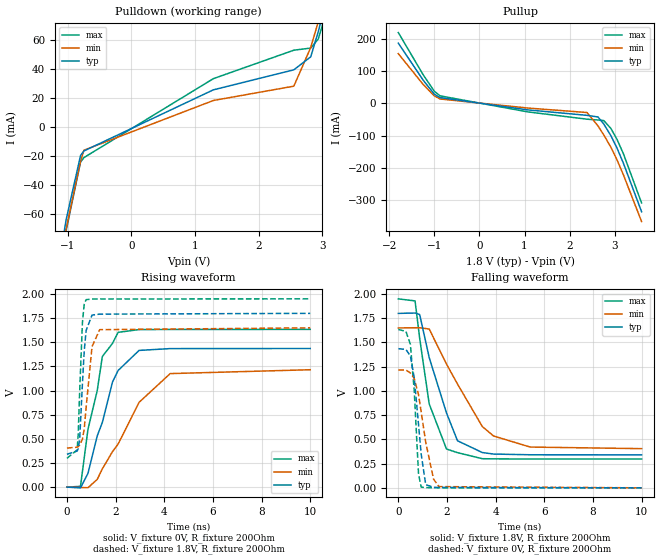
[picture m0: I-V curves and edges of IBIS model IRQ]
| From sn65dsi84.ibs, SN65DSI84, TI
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|   Model
[Model]   IRQ
Model_type   Output
Polarity   Non-Inverting
Vmeas = 0.9
Vref = 0
Cref = 1pF
Rref = 10000
|   typ   min   max
C_comp   0.2695pF   0.2096pF   0.3469pF
[Voltage Range]   1.8   1.65   1.95
[Temperature Range]   27   125   -40
[Pullup Reference]   1.8   1.65   1.95
[Pulldown Reference]   -0   -0   -0
[Power Clamp Reference]   1.8   1.65   1.95
[GND Clamp Reference]   -0   -0   -0
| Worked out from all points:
|   slope of the pulldown table from 0 to 0.27 V, typ, clamps not added: 46.5 ohm
|   slope of the pullup table from 0 to 0.27 V, typ, clamps not added: 50.4 ohm
|   falling waveform, V_fixture 1.8V, R_fixture 200Ohm: 20-80 % time 1.04ns typ, 1.66ns min, 767ps max; typ from 1.8 V to 0.341 V
|   rising waveform, V_fixture 0V, R_fixture 200Ohm: 20-80 % time 974ps typ, 1.78ns min, 693ps max; typ from 0 V to 1.44 V
|   rising waveform, V_fixture 1.8V, R_fixture 200Ohm: 20-80 % time 183ps typ, 265ps min, 143ps max; typ from 0.341 V to 1.8 V
|   falling waveform, V_fixture 0V, R_fixture 200Ohm: 20-80 % time 314ps typ, 477ps min, 223ps max; typ from 1.44 V to 0 V
[Pulldown]
|   Voltage   I(typ)   I(min)   I(max)
-1.8V     -333mA     -309.7mA   -367.4mA
-1.157V   -99.32mA   -101.7mA   -114.1mA
-1.022V   -63.77mA   -69.97mA   -71.37mA
-795.6mV  -19.54mA   -23.42mA   -24.05mA
-741.6mV  -16.41mA   -15.88mA   -20.97mA
1.289V    25.61mA    18.28mA    33.3mA
2.552V    39.37mA    28.13mA    52.87mA
2.817V    48.31mA    54.73mA    54.33mA
2.936V    65.68mA    72.46mA    60.58mA
3.022V    80.75mA    86.06mA    73.32mA
3.071V    89.66mA    93.88mA    82.17mA
3.595V    192.5mA    182mA      195.1mA
[Pullup]
|   Voltage   I(typ)   I(min)   I(max)
-1.8V     186.6mA    154.1mA    219.3mA
-1.249V   72.09mA    58.72mA    88.81mA
-1.001V   28.48mA    23.16mA    37.43mA
-871.2mV  17.99mA    13.71mA    23.36mA
1.062V    -19.91mA   -14.15mA   -26mA
2.385V    -36.91mA   -28.19mA   -48.82mA
2.628V    -41.93mA   -69.51mA   -51.27mA
2.758V    -64.03mA   -97.92mA   -53.23mA
2.914V    -99.8mA    -135.6mA   -77.48mA
3.049V    -137.9mA   -174.4mA   -111mA
3.19V     -184.6mA   -220.4mA   -155.2mA
3.595V    -335.4mA   -365.7mA   -308.2mA
[Ramp]
R_load = 200
|   typ   min   max
dV/dt_r   0.861892/9.76011e-10   0.729729/1.75843e-09   0.980234/6.94517e-10
dV/dt_f   0.875592/1.04381e-09   0.74723/1.6614e-09   0.991498/7.69733e-10
[Falling Waveform]
V_fixture = 1.8V
V_fixture_min = 1.65V
V_fixture_max = 1.95V
R_fixture = 200Ohm
C_fixture = 0F
|   Time   V(typ)   V(min)   V(max)
0s        1.8V       1.65V      1.95V
688.8ps   1.804V     1.652V     1.929V
878.6ps   1.788V     1.652V     1.542V
1.269ns   1.345V     1.639V     866.8mV
1.98ns    773.2mV    1.278V     400.9mV
2.433ns   485.8mV    1.071V     363.2mV
3.452ns   364.5mV    633mV      300.9mV
3.913ns   348.7mV    535.4mV    299.1mV
5.421ns   341.3mV    420.9mV    297.5mV
10ns      340.7mV    404.5mV    297.5mV
[Rising Waveform]
V_fixture = 0V
V_fixture_min = 0V
V_fixture_max = 0V
R_fixture = 200Ohm
C_fixture = 0F
|   Time   V(typ)   V(min)   V(max)
0s        62.16nV    120uV      254.8nV
556.8ps   -7.315mV   -3.762mV   8.38mV
864.8ps   142.5mV    -5.909mV   600mV
1.244ns   529.9mV    79.93mV    998.9mV
1.455ns   669.9mV    189mV      1.353V
1.873ns   1.089V     368.3mV    1.489V
2.103ns   1.208V     446.3mV    1.603V
2.964ns   1.416V     878.1mV    1.632V
4.245ns   1.435V     1.176V     1.633V
10ns      1.436V     1.216V     1.634V
[Rising Waveform]
V_fixture = 1.8V
V_fixture_min = 1.65V
V_fixture_max = 1.95V
R_fixture = 200Ohm
C_fixture = 0F
|   Time   V(typ)   V(min)   V(max)
0s        340.7mV    404.5mV    297.5mV
420ps     373.3mV    413.6mV    387.1mV
461.5ps   396.6mV    418.6mV    540.7mV
524ps     500.2mV    435.1mV    996.3mV
636.5ps   1.069V     496.6mV    1.705V
710.1ps   1.41V      602.3mV    1.896V
788.7ps   1.623V     825.1mV    1.942V
1.031ns   1.782V     1.456V     1.948V
1.347ns   1.792V     1.631V     1.949V
10ns      1.8V       1.65V      1.95V
[Falling Waveform]
|Gnd
V_fixture = 0V
V_fixture_min = 0V
V_fixture_max = 0V
R_fixture = 200Ohm
C_fixture = 0F
|   Time   V(typ)   V(min)   V(max)
0s        1.436V     1.216V     1.634V
311.8ps   1.428V     1.216V     1.615V
496.9ps   1.361V     1.185V     1.481V
654.9ps   1.137V     1.127V     1.001V
831.4ps   651.9mV    961.3mV    141.8mV
942.1ps   345mV      780.9mV    7.068mV
1.127ns   32.18mV    470.2mV    3.116mV
1.45ns    5.693mV    88.88mV    790.7uV
1.674ns   4.342mV    12.77mV    770uV
10ns      62.02nV    120.2uV    254.7nV
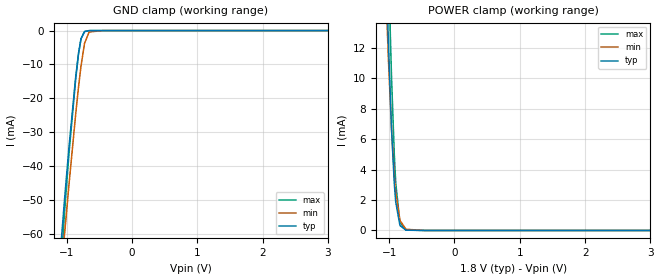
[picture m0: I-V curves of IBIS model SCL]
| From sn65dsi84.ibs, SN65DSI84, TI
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|   Model
[Model]   SCL
Model_type   Input
Vinl = 0.54
Vinh = 1.26
|   typ   min   max
C_comp   0.1891pF   0.1144pF   0.2684pF
[Voltage Range]   1.8   1.65   1.95
[Temperature Range]   27   125   -40
[Power Clamp Reference]   1.8   1.65   1.95
[GND Clamp Reference]   -0   -0   -0
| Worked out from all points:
|   GND clamp passes 1 mA (typ) near -0.75 V on its own axis
|   POWER clamp passes 1 mA (typ) near -0.87 V on its own axis
[GND Clamp]
|   Voltage   I(typ)   I(min)   I(max)
-1.8V     -308mA     -292.1mA   -326.9mA
-1.141V   -77.87mA   -84.93mA   -86.79mA
-1.087V   -63.42mA   -72.55mA   -69.8mA
-1.033V   -50.21mA   -60.55mA   -54.19mA
-963mV    -34.35mA   -45.43mA   -36.28mA
-860.4mV  -13.64mA   -24.61mA   -14.26mA
-817.2mV  -6.639mA   -16.67mA   -6.881mA
-779.4mV  -2.431mA   -10.48mA   -2.438mA
-725.4mV  -281.1uA   -3.796mA   -288.1uA
-655.2mV  -11.59uA   -427.7uA   -18.55uA
-450mV    -689.2pA   -165.9nA   -3.991nA
3.595V    0A         0A         0A
[POWER Clamp]
|   Voltage   I(typ)   I(min)   I(max)
-1.8V     160.5mA    134.1mA    187.1mA
-1.071V   21.35mA    18.46mA    28.34mA
-1.044V   17.18mA    15.11mA    23.34mA
-1.033V   15.58mA    13.84mA    21.4mA
-1.012V   12.54mA    11.4mA     17.66mA
-963mV    6.674mA    6.673mA    10.11mA
-919.8mV  3.033mA    3.571mA    4.947mA
-898.2mV  1.861mA    2.46mA     3.112mA
-833.4mV  322.4uA    654.5uA    513uA
-741.6mV  20.48uA    76.69uA    25.35uA
-450mV    1.308nA    64.32nA    622.8pA
3.595V    0A         0A         0A
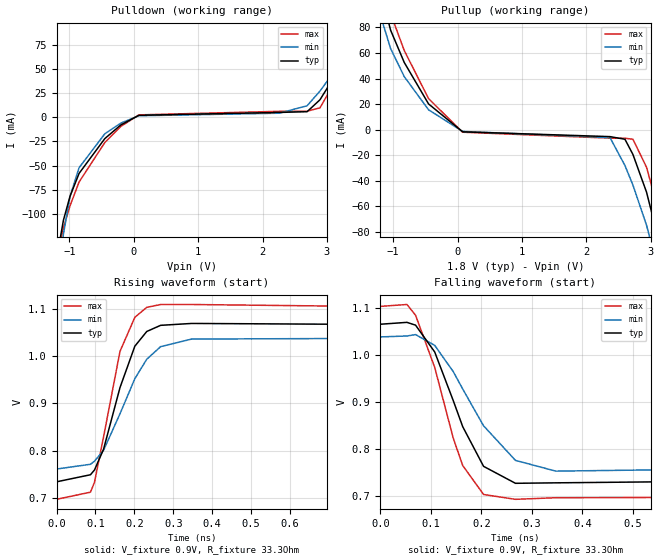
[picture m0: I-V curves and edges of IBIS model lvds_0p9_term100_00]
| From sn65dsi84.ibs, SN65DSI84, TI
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|   Model
[Model]   lvds_0p9_term100_00
Model_type   Output
Polarity   Non-Inverting
Vmeas = 0.9
Vref = 0.9
Cref = 1pF
Rref = 50
|   typ   min   max
C_comp   0.4797pF   0.3035pF   0.7186pF
[Voltage Range]   1.8   1.65   1.95
[Temperature Range]   27   125   -40
[Pullup Reference]   1.8   1.65   1.95
[Pulldown Reference]   -0   -0   -0
[Power Clamp Reference]   1.8   1.65   1.95
[GND Clamp Reference]   -0   -0   -0
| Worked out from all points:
|   slope of the pulldown table from 0 to 0.27 V, typ, clamps not added: 62.1 ohm
|   slope of the pullup table from 0 to 0.27 V, typ, clamps not added: 74.8 ohm
|   falling waveform, V_fixture 0.9V, R_fixture 33.3Ohm: 20-80 % time 71.2ps typ, 91.9ps min, 64.4ps max; typ from 1.06 V to 0.734 V
|   rising waveform, V_fixture 0.9V, R_fixture 33.3Ohm: 20-80 % time 70.3ps typ, 92ps min, 57.9ps max; typ from 0.734 V to 1.07 V
[Pulldown]
|   Voltage   I(typ)   I(min)   I(max)
-1.8V     -663.2mA   -698.2mA   -653.8mA
-1.147V   -127.1mA   -150.5mA   -131.3mA
-1.093V   -106.7mA   -121.2mA   -114.7mA
-990mV    -81.79mA   -82mA      -91.67mA
-849.6mV  -58.11mA   -52.24mA   -67.04mA
-450mV    -22.08mA   -17.11mA   -26.18mA
-201.6mV  -7.915mA   -6.02mA    -9.483mA
79.2mV    2.069mA    1.602mA    2.511mA
2.261V    5.055mA    4.263mA    6.221mA
2.693V    5.825mA    11.99mA    6.265mA
2.893V    18.2mA     27.2mA     9.845mA
3.595V    93.41mA    90.88mA    91.31mA
[Pullup]
|   Voltage   I(typ)   I(min)   I(max)
-1.8V     238.4mA    204.8mA    267.3mA
-1.406V   147.9mA    123.5mA    169.1mA
-1.039V   77.79mA    63.39mA    90.82mA
-828mV    52.64mA    41.57mA    61.97mA
-450mV    20.19mA    15.6mA     24.32mA
79.2mV    -1.629mA   -1.318mA   -1.926mA
2.369V    -5.381mA   -6.136mA   -6.594mA
2.601V    -7.44mA    -27.97mA   -6.64mA
2.725V    -19.31mA   -43.25mA   -7.414mA
2.936V    -48.73mA   -74.55mA   -29.26mA
3.13V     -87.11mA   -112.3mA   -64.81mA
3.595V    -191.5mA   -213.4mA   -169.3mA
[Ramp]
R_load = 33.3
|   typ   min   max
dV/dt_r   0.198677/7.02874e-11   0.166166/9.20302e-11   0.243302/5.78686e-11
dV/dt_f   0.198434/7.11772e-11   0.166017/9.18975e-11   0.24332/6.44189e-11
[Falling Waveform]
V_fixture = 0.9V
V_fixture_min = 0.9V
V_fixture_max = 0.9V
R_fixture = 33.3Ohm
C_fixture = 0F
|   Time   V(typ)   V(min)   V(max)
0s        1.065V     1.038V     1.103V
52.82ps   1.069V     1.04V      1.107V
69.85ps   1.063V     1.043V     1.084V
107.7ps   1.006V     1.02V      973.2mV
144.4ps   902.5mV    964.2mV    822.6mV
163.1ps   847.1mV    927.2mV    764.4mV
204.4ps   762.6mV    848.9mV    702.7mV
267.5ps   726.5mV    775.3mV    692.4mV
347.4ps   727.5mV    752.4mV    695.8mV
1ns       734.4mV    761.4mV    697.4mV
[Rising Waveform]
V_fixture = 0.9V
V_fixture_min = 0.9V
V_fixture_max = 0.9V
R_fixture = 33.3Ohm
C_fixture = 0F
|   Time   V(typ)   V(min)   V(max)
0s        734.5mV    761.5mV    697.5mV
87.21ps   749.4mV    771.5mV    712.6mV
97.65ps   759.6mV    778.1mV    733.7mV
120.8ps   803.1mV    801mV      828.9mV
163.1ps   933.5mV    878.2mV    1.01V
201.3ps   1.021V     952.4mV    1.082V
231.9ps   1.052V     993.4mV    1.103V
267.5ps   1.065V     1.02V      1.109V
347.4ps   1.069V     1.036V     1.109V
1ns       1.066V     1.038V     1.103V
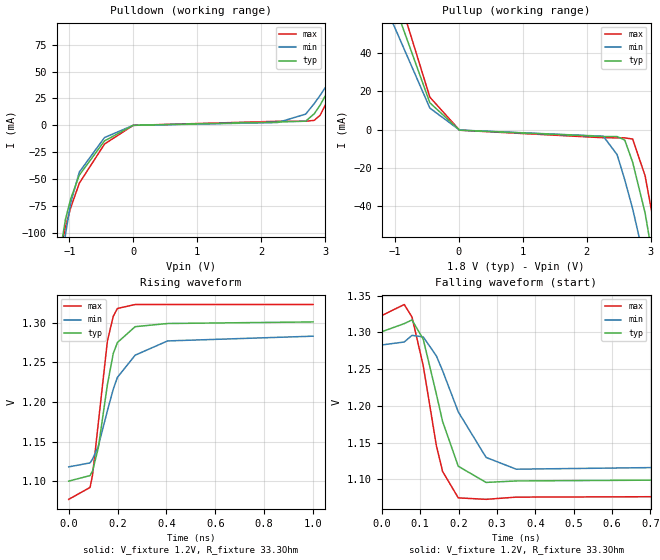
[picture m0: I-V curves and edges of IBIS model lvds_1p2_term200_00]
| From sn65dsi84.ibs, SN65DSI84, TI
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|   Model
[Model]   lvds_1p2_term200_00
Model_type   Output
Polarity   Non-Inverting
Vmeas = 1.2
Vref = 1.2
Cref = 1pF
Rref = 50
|   typ   min   max
C_comp   0.4797pF   0.3035pF   0.7186pF
[Voltage Range]   1.8   1.65   1.95
[Temperature Range]   27   125   -40
[Pullup Reference]   1.8   1.65   1.95
[Pulldown Reference]   -0   -0   -0
[Power Clamp Reference]   1.8   1.65   1.95
[GND Clamp Reference]   -0   -0   -0
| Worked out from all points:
|   slope of the pulldown table from 0 to 0.27 V, typ, clamps not added: 103 ohm
|   slope of the pullup table from 0 to 0.27 V, typ, clamps not added: 114 ohm
|   falling waveform, V_fixture 1.2V, R_fixture 33.3Ohm: 20-80 % time 56.1ps typ, 82.7ps min, 49.8ps max; typ from 1.3 V to 1.1 V
|   rising waveform, V_fixture 1.2V, R_fixture 33.3Ohm: 20-80 % time 62.1ps typ, 110ps min, 51.8ps max; typ from 1.1 V to 1.3 V
[Pulldown]
|   Voltage   I(typ)   I(min)   I(max)
-1.8V     -662.7mA   -697.8mA   -653.1mA
-1.13V    -112.7mA   -137.9mA   -115.4mA
-1.06V    -87.36mA   -101.6mA   -94.27mA
-979.2mV  -68.51mA   -72.26mA   -76.75mA
-844.2mV  -46.38mA   -43.5mA    -53.83mA
-450mV    -14.51mA   -11.38mA   -17.44mA
-1.8mV    -33.52uA   -25.45uA   -40.79uA
2.255V    3.03mA     2.555mA    3.73mA
2.693V    3.824mA    10.38mA    3.762mA
2.828V    10.8mA     20.31mA    4.629mA
2.92V     18.84mA    27.88mA    9.431mA
3.595V    91.51mA    89.23mA    89.04mA
[Pullup]
|   Voltage   I(typ)   I(min)   I(max)
-1.8V     228.4mA    197.8mA    256.2mA
-1.384V   134.8mA    113.2mA    154.9mA
-1.022V   67.23mA    55.25mA    78.93mA
-450mV    14.1mA     11.33mA    17.03mA
14.4mV    -217.5uA   -179.5uA   -252uA
2.261V    -3.537mA   -3.389mA   -4.176mA
2.477V    -3.566mA   -13.07mA   -4.203mA
2.596V    -5.396mA   -26.18mA   -4.219mA
2.72V     -17.05mA   -41.41mA   -4.896mA
2.914V    -43.54mA   -69.73mA   -24.09mA
3.152V    -90.28mA   -115.7mA   -67.42mA
3.595V    -190.1mA   -212.3mA   -167.4mA
[Ramp]
R_load = 33.3
|   typ   min   max
dV/dt_r   0.120214/6.20859e-11  0.0988831/1.09518e-10   0.147657/5.18256e-11
dV/dt_f   0.120287/5.61186e-11  0.0991023/8.2679e-11   0.147675/4.97948e-11
[Falling Waveform]
V_fixture = 1.2V
V_fixture_min = 1.2V
V_fixture_max = 1.2V
R_fixture = 33.3Ohm
C_fixture = 0F
|   Time   V(typ)   V(min)   V(max)
0s        1.301V     1.283V     1.323V
58.42ps   1.312V     1.287V     1.338V
78.5ps    1.317V     1.296V     1.321V
107.8ps   1.291V     1.294V     1.255V
142.2ps   1.216V     1.268V     1.146V
158.3ps   1.179V     1.248V     1.111V
199.2ps   1.118V     1.192V     1.075V
271.7ps   1.096V     1.13V      1.073V
350.3ps   1.098V     1.114V     1.076V
1ns       1.1V       1.118V     1.077V
[Rising Waveform]
V_fixture = 1.2V
V_fixture_min = 1.2V
V_fixture_max = 1.2V
R_fixture = 33.3Ohm
C_fixture = 0F
|   Time   V(typ)   V(min)   V(max)
0s        1.1V       1.118V     1.077V
87.14ps   1.107V     1.123V     1.092V
97.58ps   1.113V     1.128V     1.108V
120.9ps   1.142V     1.144V     1.173V
158.3ps   1.222V     1.189V     1.277V
182.1ps   1.261V     1.216V     1.308V
199.2ps   1.275V     1.231V     1.318V
271.7ps   1.295V     1.259V     1.323V
404.4ps   1.299V     1.277V     1.323V
1ns       1.301V     1.283V     1.323V
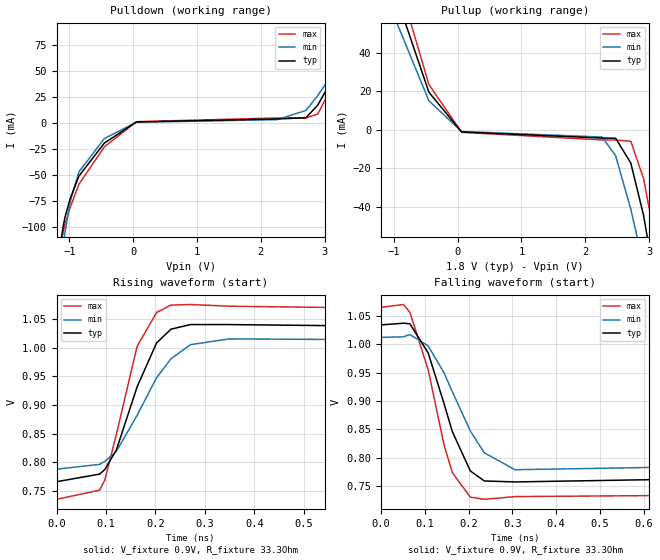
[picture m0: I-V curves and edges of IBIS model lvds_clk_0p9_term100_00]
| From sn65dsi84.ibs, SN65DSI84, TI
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|   Model
[Model]   lvds_clk_0p9_term100_00
Model_type   Output
Polarity   Non-Inverting
Vmeas = 0.9
Vref = 0.9
Cref = 1pF
Rref = 50
|   typ   min   max
C_comp   0.4797pF   0.3035pF   0.7186pF
[Voltage Range]   1.8   1.65   1.95
[Temperature Range]   27   125   -40
[Pullup Reference]   1.8   1.65   1.95
[Pulldown Reference]   -0   -0   -0
[Power Clamp Reference]   1.8   1.65   1.95
[GND Clamp Reference]   -0   -0   -0
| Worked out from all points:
|   slope of the pulldown table from 0 to 0.27 V, typ, clamps not added: 76.3 ohm
|   slope of the pullup table from 0 to 0.27 V, typ, clamps not added: 92.1 ohm
|   falling waveform, V_fixture 0.9V, R_fixture 33.3Ohm: 20-80 % time 65.1ps typ, 82.8ps min, 58.7ps max; typ from 1.03 V to 0.766 V
|   rising waveform, V_fixture 0.9V, R_fixture 33.3Ohm: 20-80 % time 65.2ps typ, 87.1ps min, 53.3ps max; typ from 0.766 V to 1.03 V
[Pulldown]
|   Voltage   I(typ)   I(min)   I(max)
-1.8V     -662.6mA   -697.8mA   -653.1mA
-1.13V    -112.8mA   -137.8mA   -115.6mA
-1.093V   -98.16mA   -117.2mA   -103.8mA
-1.066V   -89.99mA   -104.3mA   -97.08mA
-984.6mV  -72.24mA   -75.1mA    -80.79mA
-849.6mV  -50.82mA   -46.82mA   -58.68mA
-450mV    -19.06mA   -14.73mA   -22.65mA
52.2mV    1.211mA    935.7uA    1.469mA
2.261V    4.084mA    3.439mA    5.042mA
2.709V    5.234mA    12.28mA    5.089mA
2.893V    17.31mA    26.43mA    8.728mA
3.595V    92.49mA    90.08mA    90.23mA
[Pullup]
|   Voltage   I(typ)   I(min)   I(max)
-1.8V     237.6mA    203.9mA    266.4mA
-1.411V   148mA      123.6mA    169.4mA
-1.039V   76.94mA    62.59mA    89.89mA
-450mV    19.51mA    15.04mA    23.53mA
63mV      -1.148mA   -931.1uA   -1.345mA
2.266V    -4.318mA   -3.801mA   -5.289mA
2.477V    -4.419mA   -13.5mA    -5.359mA
2.714V    -17.27mA   -41.2mA    -6.003mA
2.914V    -44.4mA    -70.26mA   -25.28mA
3.103V    -80.8mA    -106.2mA   -58.44mA
3.163V    -93.5mA    -118.6mA   -70.88mA
3.595V    -191.2mA   -213.1mA   -168.7mA
[Ramp]
R_load = 33.3
|   typ   min   max
dV/dt_r   0.160952/6.51744e-11   0.134803/8.70959e-11   0.197638/5.32723e-11
dV/dt_f   0.160717/6.51386e-11   0.134547/8.28133e-11   0.19766/5.86534e-11
[Falling Waveform]
V_fixture = 0.9V
V_fixture_min = 0.9V
V_fixture_max = 0.9V
R_fixture = 33.3Ohm
C_fixture = 0F
|   Time   V(typ)   V(min)   V(max)
0s        1.034V     1.012V     1.065V
51.23ps   1.037V     1.013V     1.07V
65.99ps   1.036V     1.017V     1.056V
107.7ps   984.6mV    997mV      954.9mV
144.3ps   894.3mV    949mV      821.2mV
163ps     845.6mV    916mV      773.3mV
204.1ps   776.4mV    846.8mV    730.2mV
235.9ps   758.8mV    808.5mV    726.4mV
306.1ps   757.1mV    778.6mV    731.2mV
1ns       766mV      787.7mV    735.2mV
[Rising Waveform]
V_fixture = 0.9V
V_fixture_min = 0.9V
V_fixture_max = 0.9V
R_fixture = 33.3Ohm
C_fixture = 0F
|   Time   V(typ)   V(min)   V(max)
0s        766mV      787.8mV    735.3mV
87.21ps   779.3mV    796.3mV    751.3mV
97.67ps   787.3mV    801.4mV    768.8mV
120.9ps   821.1mV    818.7mV    848mV
163ps     931.4mV    881.8mV    1.002V
202.3ps   1.008V     947.3mV    1.061V
231.5ps   1.032V     980.4mV    1.074V
271ps     1.04V      1.005V     1.075V
349.4ps   1.04V      1.015V     1.072V
1ns       1.034V     1.012V     1.065V
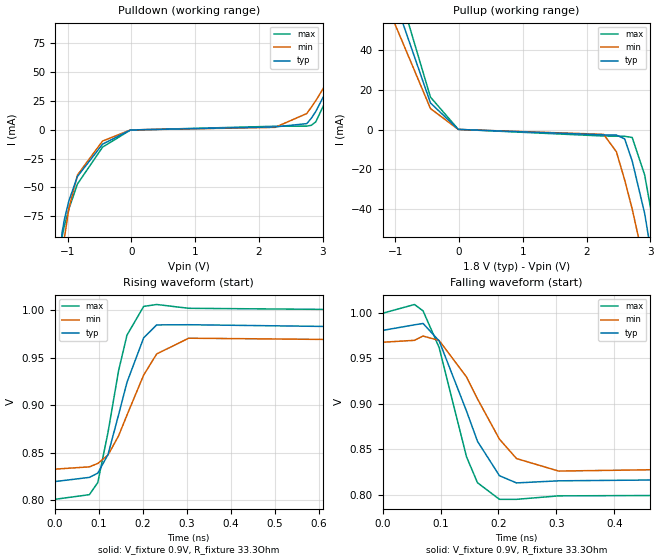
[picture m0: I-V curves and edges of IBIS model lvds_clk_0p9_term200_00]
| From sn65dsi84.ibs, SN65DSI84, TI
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|   Model
[Model]   lvds_clk_0p9_term200_00
Model_type   Output
Polarity   Non-Inverting
Vmeas = 0.9
Vref = 0.9
Cref = 1pF
Rref = 50
|   typ   min   max
C_comp   0.4797pF   0.3035pF   0.7186pF
[Voltage Range]   1.8   1.65   1.95
[Temperature Range]   27   125   -40
[Pullup Reference]   1.8   1.65   1.95
[Pulldown Reference]   -0   -0   -0
[Power Clamp Reference]   1.8   1.65   1.95
[GND Clamp Reference]   -0   -0   -0
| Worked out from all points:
|   slope of the pulldown table from 0 to 0.27 V, typ, clamps not added: 127 ohm
|   slope of the pullup table from 0 to 0.27 V, typ, clamps not added: 154 ohm
|   falling waveform, V_fixture 0.9V, R_fixture 33.3Ohm: 20-80 % time 55.1ps typ, 68.7ps min, 47.4ps max; typ from 0.981 V to 0.82 V
|   rising waveform, V_fixture 0.9V, R_fixture 33.3Ohm: 20-80 % time 56.7ps typ, 76.8ps min, 47.6ps max; typ from 0.82 V to 0.981 V
[Pulldown]
|   Voltage   I(typ)   I(min)   I(max)
-1.8V     -662.3mA   -697.6mA   -652.6mA
-1.087V   -89.57mA   -111.6mA   -93.11mA
-1.049V   -77.61mA   -93.69mA   -83.11mA
-979.2mV  -61.67mA   -68.27mA   -68.63mA
-844.2mV  -40.44mA   -39.16mA   -46.96mA
-450mV    -12.48mA   -9.755mA   -15.02mA
-12.6mV   -201.7uA   -153.6uA   -245.1uA
2.255V    2.45mA     2.064mA    3.025mA
2.752V    5.292mA    14.03mA    3.13mA
2.822V    9.84mA     19.42mA    3.81mA
2.893V    15.8mA     25.15mA    6.822mA
3.595V    90.97mA    88.75mA    88.4mA
[Pullup]
|   Voltage   I(typ)   I(min)   I(max)
-1.8V     227.7mA    196.9mA    255.5mA
-1.39V    135.1mA    113.1mA    155.4mA
-1.022V   66.49mA    54.34mA    78.23mA
-450mV    13.5mA     10.68mA    16.42mA
-12.6mV   167.1uA    131.7uA    196.7uA
2.266V    -2.587mA   -2.309mA   -3.171mA
2.466V    -2.672mA   -11.08mA   -3.224mA
2.596V    -4.606mA   -25.31mA   -3.294mA
2.714V    -15.73mA   -39.89mA   -3.909mA
2.909V    -42.04mA   -68.08mA   -22.68mA
3.136V    -86.3mA    -111.7mA   -63.45mA
3.595V    -189.8mA   -212mA     -167mA
[Ramp]
R_load = 33.3
|   typ   min   max
dV/dt_r   0.096664/5.66709e-11  0.0809776/7.68463e-11   0.119148/4.75678e-11
dV/dt_f   0.0966321/5.51163e-11  0.0809772/6.86759e-11   0.119149/4.73592e-11
[Falling Waveform]
V_fixture = 0.9V
V_fixture_min = 0.9V
V_fixture_max = 0.9V
R_fixture = 33.3Ohm
C_fixture = 0F
|   Time   V(typ)   V(min)   V(max)
0s        980.6mV    967.6mV    999.4mV
55.03ps   986.7mV    969.7mV    1.009V
69.85ps   988.2mV    974.4mV    1.002V
97.68ps   969mV      969.5mV    961.7mV
144.9ps   892.1mV    929.5mV    841.9mV
163.9ps   858.9mV    905.4mV    813.5mV
201.8ps   821.2mV    861.3mV    795.3mV
231.3ps   813.3mV    840mV      795.3mV
304ps     815.6mV    826.3mV    799.1mV
1ns       819.5mV    832.6mV    800.8mV
[Rising Waveform]
V_fixture = 0.9V
V_fixture_min = 0.9V
V_fixture_max = 0.9V
R_fixture = 33.3Ohm
C_fixture = 0F
|   Time   V(typ)   V(min)   V(max)
0s        819.5mV    832.6mV    800.8mV
78.53ps   823.9mV    835mV      805.7mV
97.68ps   828.4mV    838.6mV    818.5mV
120.9ps   848.1mV    847.5mV    871.5mV
144.9ps   889.9mV    867.7mV    936.4mV
163.9ps   924mV      889.5mV    973.7mV
201.8ps   970.9mV    931.7mV    1.004V
231.3ps   984.5mV    953.9mV    1.006V
304ps     984.7mV    970.5mV    1.002V
1ns       980.6mV    967.6mV    999.4mV
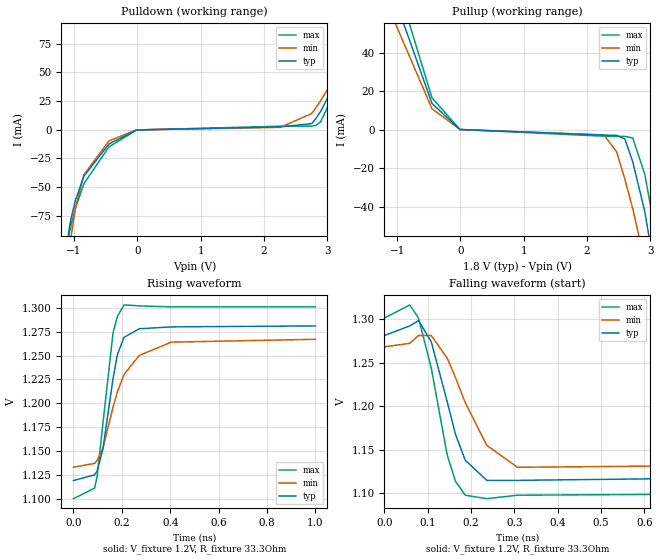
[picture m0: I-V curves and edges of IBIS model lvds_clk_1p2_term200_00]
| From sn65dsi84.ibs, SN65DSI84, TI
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|   Model
[Model]   lvds_clk_1p2_term200_00
Model_type   Output
Polarity   Non-Inverting
Vmeas = 1.2
Vref = 1.2
Cref = 1pF
Rref = 50
|   typ   min   max
C_comp   0.4797pF   0.3035pF   0.7186pF
[Voltage Range]   1.8   1.65   1.95
[Temperature Range]   27   125   -40
[Pullup Reference]   1.8   1.65   1.95
[Pulldown Reference]   -0   -0   -0
[Power Clamp Reference]   1.8   1.65   1.95
[GND Clamp Reference]   -0   -0   -0
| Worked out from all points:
|   slope of the pulldown table from 0 to 0.27 V, typ, clamps not added: 127 ohm
|   slope of the pullup table from 0 to 0.27 V, typ, clamps not added: 142 ohm
|   falling waveform, V_fixture 1.2V, R_fixture 33.3Ohm: 20-80 % time 51.6ps typ, 73.6ps min, 45.7ps max; typ from 1.28 V to 1.12 V
|   rising waveform, V_fixture 1.2V, R_fixture 33.3Ohm: 20-80 % time 58.4ps typ, 105ps min, 49.8ps max; typ from 1.12 V to 1.28 V
[Pulldown]
|   Voltage   I(typ)   I(min)   I(max)
-1.8V     -662.3mA   -697.6mA   -652.6mA
-1.087V   -89.57mA   -111.6mA   -93.11mA
-1.049V   -77.61mA   -93.69mA   -83.11mA
-979.2mV  -61.66mA   -68.26mA   -68.63mA
-844.2mV  -40.44mA   -39.16mA   -46.96mA
-450mV    -12.48mA   -9.753mA   -15.02mA
-12.6mV   -201.6uA   -153.5uA   -245uA
2.255V    2.448mA    2.061mA    3.023mA
2.752V    5.29mA     14.03mA    3.129mA
2.822V    9.838mA    19.42mA    3.809mA
2.893V    15.8mA     25.15mA    6.821mA
3.595V    90.96mA    88.75mA    88.4mA
[Pullup]
|   Voltage   I(typ)   I(min)   I(max)
-1.8V     227.9mA    197.2mA    255.6mA
-1.39V    135.3mA    113.5mA    155.5mA
-1.022V   66.66mA    54.68mA    78.37mA
-450mV    13.65mA    10.92mA    16.56mA
-7.2mV    98.85uA    81.53uA    115uA
2.266V    -2.807mA   -2.716mA   -3.375mA
2.466V    -2.892mA   -11.45mA   -3.429mA
2.596V    -4.815mA   -25.67mA   -3.5mA
2.72V     -16.55mA   -40.94mA   -4.257mA
2.909V    -42.23mA   -68.43mA   -22.86mA
3.136V    -86.48mA   -112.1mA   -63.62mA
3.595V    -190mA     -212.3mA   -167.2mA
[Ramp]
R_load = 33.3
|   typ   min   max
dV/dt_r   0.0969846/5.83938e-11  0.0805656/1.04539e-10   0.120207/4.9795e-11
dV/dt_f   0.0970188/5.15956e-11  0.0807274/7.36274e-11   0.120216/4.5655e-11
[Falling Waveform]
V_fixture = 1.2V
V_fixture_min = 1.2V
V_fixture_max = 1.2V
R_fixture = 33.3Ohm
C_fixture = 0F
|   Time   V(typ)   V(min)   V(max)
0s        1.281V     1.268V     1.301V
58.42ps   1.292V     1.272V     1.316V
78.51ps   1.298V     1.281V     1.301V
107.8ps   1.274V     1.281V     1.244V
144.8ps   1.205V     1.255V     1.144V
163.7ps   1.168V     1.233V     1.114V
186.4ps   1.138V     1.204V     1.098V
236.3ps   1.115V     1.155V     1.094V
306.9ps   1.115V     1.13V      1.098V
1ns       1.119V     1.133V     1.1V
[Rising Waveform]
V_fixture = 1.2V
V_fixture_min = 1.2V
V_fixture_max = 1.2V
R_fixture = 33.3Ohm
C_fixture = 0F
|   Time   V(typ)   V(min)   V(max)
0s        1.119V     1.133V     1.1V
87.17ps   1.125V     1.137V     1.111V
97.63ps   1.129V     1.14V      1.123V
120.9ps   1.151V     1.152V     1.177V
163.7ps   1.226V     1.196V     1.274V
181.6ps   1.251V     1.212V     1.291V
209ps     1.269V     1.23V      1.303V
271.6ps   1.278V     1.25V      1.302V
404.4ps   1.28V      1.264V     1.301V
1ns       1.281V     1.267V     1.301V
